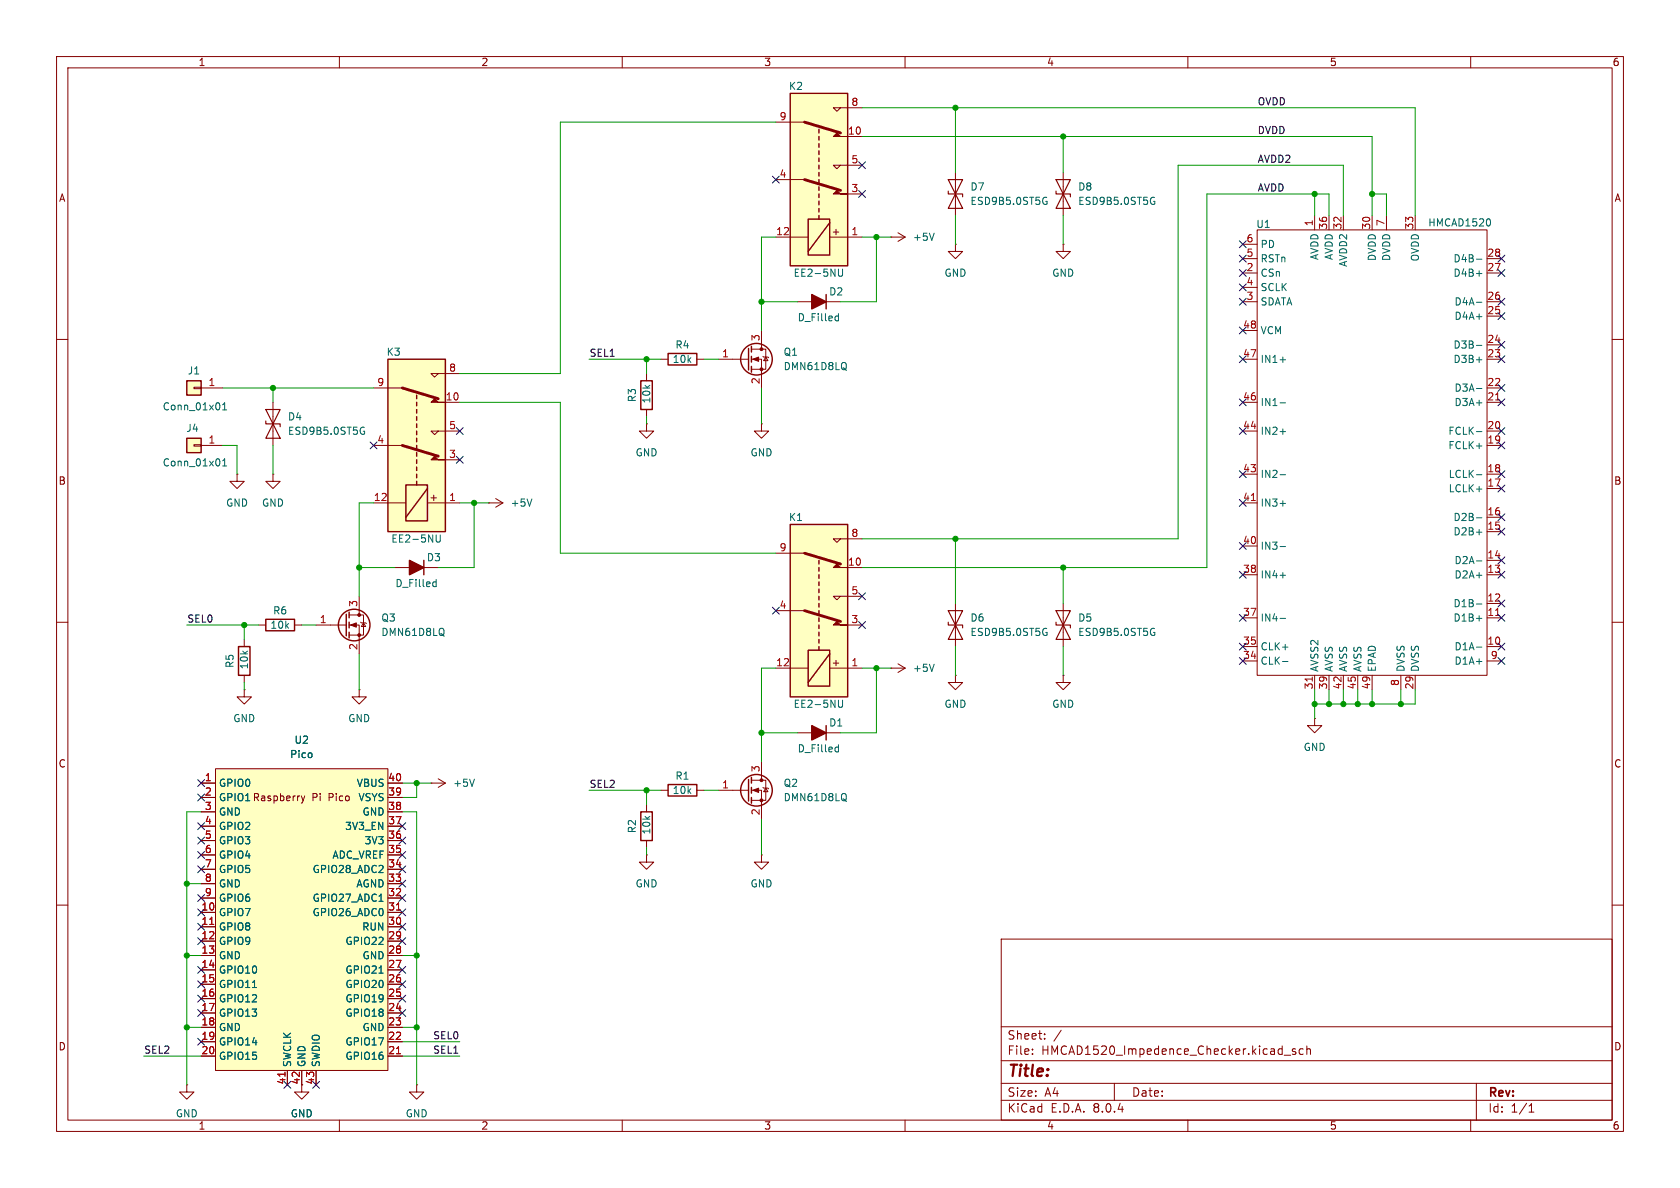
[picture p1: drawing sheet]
<svg xmlns="http://www.w3.org/2000/svg" width="297mm" height="210mm" viewBox="0 0 297 210" stroke-linecap="round" stroke-linejoin="round" font-family="sans-serif">
<defs><g id="words">
<text font-size="2.8" fill="#840000" x="178" y="190.9">Title:</text>
<g font-size="2.1" fill="#840000">
<text x="178" y="184">Sheet:</text>
<text x="178" y="186.7">File:</text>
<text x="184.1" y="186.7">HMCAD1520_Impedence_Checker.kicad_sch</text>
<text x="178" y="196.9">KiCad</text>
<text x="178" y="194.1">Size:</text>
<text x="184.7" y="194.1">A4</text>
<text x="185.7" y="196.9">E.D.A.</text>
<text x="193.3" y="196.9">8.0.4</text>
<text x="200" y="194.1">Date:</text>
<text x="263" y="194.3">Rev:</text>
<text x="263" y="196.9">Id:</text>
<text x="267.1" y="196.9">1/1</text>
</g>
<g font-size="1.8" fill="#840000">
<text x="35" y="11.9">1</text>
<text x="85" y="11.9">2</text>
<text x="135" y="11.9">3</text>
<text x="185" y="11.9">4</text>
<text x="235" y="11.9">5</text>
<text x="285" y="11.9">6</text>
<text x="10.3" y="35.9">A</text>
<text x="285.3" y="35.9">A</text>
<text x="148.6" y="41.9" transform="rotate(-90 148.6 41.9)">+</text>
<text x="10.3" y="85.9">B</text>
<text x="77.5" y="88.9" transform="rotate(-90 77.5 88.9)">+</text>
<text x="285.3" y="85.9">B</text>
<text x="148.6" y="118.1" transform="rotate(-90 148.6 118.1)">+</text>
<text x="10.3" y="135.9">C</text>
<text x="285.3" y="135.9">C</text>
<text x="38.6" y="141.8">GPIO1 Raspberry</text>
<text x="55.1" y="141.8">Pi</text>
<text x="58.2" y="141.8">Pico</text>
<text x="10.3" y="185.9">D</text>
<text x="285.3" y="185.9">D</text>
<text x="53.1" y="191.8" transform="rotate(-90 53.1 191.8)">42</text>
<text x="35" y="199.9">1</text>
<text x="85" y="199.9">2</text>
<text x="135" y="199.9">3</text>
<text x="185" y="199.9">4</text>
<text x="235" y="199.9">5</text>
<text x="285" y="199.9">6</text>
</g>
<g font-size="1.8" fill="#006464">
<text x="139.4" y="16.1">K2</text>
<text x="171.5" y="33.9">D7</text>
<text x="190.5" y="33.9">D8</text>
<text x="171.5" y="36.4">ESD9B5.0ST5G</text>
<text x="190.5" y="36.4">ESD9B5.0ST5G</text>
<text x="222" y="40.5">U1</text>
<text x="252.4" y="40.2">HMCAD1520</text>
<text x="161.3" y="42.8">+5V</text>
<text x="222.8" y="46.6">RSTn</text>
<text x="222.8" y="44">PD</text>
<text x="233.3" y="46.1" transform="rotate(-90 233.3 46.1)">AVDD</text>
<text x="235.8" y="46.1" transform="rotate(-90 235.8 46.1)">AVDD</text>
<text x="238.4" y="47.3" transform="rotate(-90 238.4 47.3)">AVDD2</text>
<text x="243.4" y="46.2" transform="rotate(-90 243.4 46.2)">DVDD</text>
<text x="246" y="46.2" transform="rotate(-90 246 46.2)">DVDD</text>
<text x="251.1" y="46.3" transform="rotate(-90 251.1 46.3)">OVDD</text>
<text x="256.9" y="46.6">D4B-</text>
<text x="140.2" y="49.1">EE2-5NU</text>
<text x="146.5" y="52.4">D2</text>
<text x="166.9" y="49.1">GND</text>
<text x="185.9" y="49.1">GND</text>
<text x="222.8" y="49.1">CSn</text>
<text x="222.8" y="51.7">SCLK</text>
<text x="256.9" y="49.1">D4B+</text>
<text x="140.9" y="57">D_Filled</text>
<text x="222.8" y="54.2">SDATA</text>
<text x="222.8" y="59.3">VCM</text>
<text x="257" y="56.7">D4A+</text>
<text x="257" y="54.2">D4A-</text>
<text x="68.3" y="63.1">K3</text>
<text x="118.8" y="64.4">10k</text>
<text x="119.3" y="61.8">R4</text>
<text x="138.4" y="63.1">Q1</text>
<text x="138.4" y="65.6">DMN61D8LQ</text>
<text x="222.8" y="64.4">IN1+</text>
<text x="256.9" y="64.4">D3B+</text>
<text x="256.9" y="61.8">D3B-</text>
<text x="33.1" y="66.4">J1</text>
<text x="112.6" y="71.2" transform="rotate(-90 112.6 71.2)">R3</text>
<text x="115.2" y="71.4" transform="rotate(-90 115.2 71.4)">10k</text>
<text x="222.8" y="72">IN1-</text>
<text x="257" y="72">D3A+</text>
<text x="257" y="69.4">D3A-</text>
<text x="28.7" y="72.7">Conn_01x01</text>
<text x="32.8" y="76.6">J4</text>
<text x="50.8" y="74.5">D4</text>
<text x="50.8" y="77.1">ESD9B5.0ST5G</text>
<text x="222.8" y="77.1">IN2+</text>
<text x="256" y="77.1">FCLK-</text>
<text x="28.7" y="82.7">Conn_01x01</text>
<text x="112.3" y="80.9">GND</text>
<text x="132.6" y="80.9">GND</text>
<text x="256" y="79.6">FCLK+</text>
<text x="39.9" y="89.8">GND</text>
<text x="46.2" y="89.8">GND</text>
<text x="90.2" y="89.8">+5V</text>
<text x="222.8" y="89.8">IN3+</text>
<text x="222.8" y="84.7">IN2-</text>
<text x="256" y="87.2">LCLK+</text>
<text x="256" y="84.7">LCLK-</text>
<text x="139.4" y="92.3">K1</text>
<text x="256.9" y="94.8">D2B+</text>
<text x="256.9" y="92.3">D2B-</text>
<text x="69.1" y="96.1">EE2-5NU</text>
<text x="75.4" y="99.4">D3</text>
<text x="222.8" y="97.4">IN3-</text>
<text x="257" y="99.9">D2A-</text>
<text x="69.8" y="104">D_Filled</text>
<text x="222.8" y="102.5">IN4+</text>
<text x="256.9" y="107.5">D1B-</text>
<text x="257" y="102.5">D2A+</text>
<text x="47.7" y="111.4">10k</text>
<text x="48.2" y="108.8">R6</text>
<text x="67.3" y="110.1">Q3</text>
<text x="67.3" y="112.6">DMN61D8LQ</text>
<text x="171.5" y="110.1">D6</text>
<text x="171.5" y="112.6">ESD9B5.0ST5G</text>
<text x="190.5" y="110.1">D5</text>
<text x="190.5" y="112.6">ESD9B5.0ST5G</text>
<text x="222.8" y="110.1">IN4-</text>
<text x="256.9" y="110.1">D1B+</text>
<text x="41.5" y="118.2" transform="rotate(-90 41.5 118.2)">R5</text>
<text x="44" y="118.4" transform="rotate(-90 44 118.4)">10k</text>
<text x="161.3" y="119">+5V</text>
<text x="222.8" y="117.7">CLK-</text>
<text x="222.8" y="115.2">CLK+</text>
<text x="233.3" y="118.9" transform="rotate(-90 233.3 118.9)">AVSS2</text>
<text x="235.8" y="118.9" transform="rotate(-90 235.8 118.9)">AVSS</text>
<text x="238.4" y="118.9" transform="rotate(-90 238.4 118.9)">AVSS</text>
<text x="240.9" y="118.9" transform="rotate(-90 240.9 118.9)">AVSS</text>
<text x="243.4" y="118.9" transform="rotate(-90 243.4 118.9)">EPAD</text>
<text x="248.5" y="118.9" transform="rotate(-90 248.5 118.9)">DVSS</text>
<text x="251.1" y="118.9" transform="rotate(-90 251.1 118.9)">DVSS</text>
<text x="257" y="115.2">D1A-</text>
<text x="257" y="117.7">D1A+</text>
<text x="140.2" y="125.3">EE2-5NU</text>
<text x="166.9" y="125.3">GND</text>
<text x="185.9" y="125.3">GND</text>
<text x="41.1" y="127.9">GND</text>
<text x="52" y="131.7">U2</text>
<text x="61.5" y="127.9">GND</text>
<text x="146.5" y="128.6">D1</text>
<text x="51.2" y="134.2">Pico</text>
<text x="140.9" y="133.2">D_Filled</text>
<text x="230.4" y="132.9">GND</text>
<text x="38.6" y="139.3">GPIO0</text>
<text x="38.6" y="141.8">GPIO1</text>
<text x="63" y="139.3">VBUS</text>
<text x="63.3" y="141.8">VSYS</text>
<text x="80" y="139.3">+5V</text>
<text x="118.8" y="140.6">10k</text>
<text x="119.3" y="138">R1</text>
<text x="138.4" y="139.3">Q2</text>
<text x="138.4" y="141.8">DMN61D8LQ</text>
<text x="38.6" y="144.4">GND</text>
<text x="38.6" y="146.9">GPIO2</text>
<text x="38.6" y="149.5">GPIO3</text>
<text x="60.9" y="146.9">3V3_EN</text>
<text x="64" y="144.4">GND</text>
<text x="64.4" y="149.5">3V3</text>
<text x="112.6" y="147.4" transform="rotate(-90 112.6 147.4)">R2</text>
<text x="115.2" y="147.6" transform="rotate(-90 115.2 147.6)">10k</text>
<text x="38.6" y="152">GPIO4</text>
<text x="38.6" y="154.5">GPIO5</text>
<text x="55.2" y="154.5">GPIO28_ADC2</text>
<text x="58.7" y="152">ADC_VREF</text>
<text x="38.6" y="157.1">GND</text>
<text x="38.6" y="159.6">GPIO6</text>
<text x="55.2" y="159.6">GPIO27_ADC1</text>
<text x="62.9" y="157.1">AGND</text>
<text x="112.3" y="157.1">GND</text>
<text x="132.6" y="157.1">GND</text>
<text x="38.6" y="162.2">GPIO7</text>
<text x="38.6" y="164.7">GPIO8</text>
<text x="38.6" y="167.2">GPIO9</text>
<text x="55.2" y="162.2">GPIO26_ADC0</text>
<text x="61" y="167.2">GPIO22</text>
<text x="63.9" y="164.7">RUN</text>
<text x="38.6" y="169.8">GND</text>
<text x="38.6" y="172.3">GPIO10</text>
<text x="61" y="172.3">GPIO21</text>
<text x="64" y="169.8">GND</text>
<text x="38.6" y="174.9">GPIO11</text>
<text x="38.6" y="177.4">GPIO12</text>
<text x="38.6" y="179.9">GPIO13</text>
<text x="61" y="179.9">GPIO18</text>
<text x="61" y="177.4">GPIO19</text>
<text x="61" y="174.9">GPIO20</text>
<text x="38.6" y="182.5">GND</text>
<text x="38.6" y="185">GPIO14</text>
<text x="61" y="185">GPIO17</text>
<text x="64" y="182.5">GND</text>
<text x="38.6" y="187.6">GPIO15</text>
<text x="51.7" y="188.7" transform="rotate(-90 51.7 188.7)">SWCLK</text>
<text x="54.2" y="188.7" transform="rotate(-90 54.2 188.7)">GND</text>
<text x="56.7" y="188.7" transform="rotate(-90 56.7 188.7)">SWDIO</text>
<text x="61" y="187.6">GPIO16</text>
<text x="31" y="197.7">GND</text>
<text x="51.3" y="197.7">GND</text>
<text x="71.6" y="197.7">GND</text>
</g>
<g font-size="1.8" fill="#a90000">
<text x="137.7" y="21.3">9</text>
<text x="149.8" y="23.9">10</text>
<text x="150.4" y="18.8">8</text>
<text x="150.4" y="29">5</text>
<text x="137.7" y="31.5">4</text>
<text x="150.4" y="34">3</text>
<text x="137.1" y="41.7">12</text>
<text x="150.4" y="41.7">1</text>
<text x="232.2" y="40.1" transform="rotate(-90 232.2 40.1)">1</text>
<text x="234.7" y="40.7" transform="rotate(-90 234.7 40.7)">36</text>
<text x="237.2" y="40.7" transform="rotate(-90 237.2 40.7)">32</text>
<text x="242.3" y="40.7" transform="rotate(-90 242.3 40.7)">30</text>
<text x="244.9" y="40.1" transform="rotate(-90 244.9 40.1)">7</text>
<text x="249.9" y="40.7" transform="rotate(-90 249.9 40.7)">33</text>
<text x="220.3" y="45.5">5</text>
<text x="220.3" y="42.9">6</text>
<text x="262.8" y="45.5">28</text>
<text x="220.3" y="48">2</text>
<text x="220.3" y="53.1">3</text>
<text x="220.3" y="50.5">4</text>
<text x="262.8" y="53.1">26</text>
<text x="262.8" y="48">27</text>
<text x="219.7" y="58.2">48</text>
<text x="262.8" y="55.6">25</text>
<text x="79.3" y="65.8">8</text>
<text x="127.6" y="63.2">1</text>
<text x="134.4" y="60.4" transform="rotate(-90 134.4 60.4)">3</text>
<text x="219.7" y="63.2">47</text>
<text x="262.8" y="63.2">23</text>
<text x="262.8" y="60.7">24</text>
<text x="36.8" y="68.3">1</text>
<text x="66.6" y="68.3">9</text>
<text x="78.7" y="70.9">10</text>
<text x="134.4" y="68" transform="rotate(-90 134.4 68)">2</text>
<text x="219.7" y="70.9">46</text>
<text x="262.8" y="70.9">21</text>
<text x="262.8" y="68.3">22</text>
<text x="79.3" y="75.9">5</text>
<text x="219.7" y="75.9">44</text>
<text x="262.8" y="75.9">20</text>
<text x="36.8" y="78.5">1</text>
<text x="66.6" y="78.5">4</text>
<text x="79.3" y="81">3</text>
<text x="219.7" y="83.6">43</text>
<text x="262.8" y="83.6">18</text>
<text x="262.8" y="78.5">19</text>
<text x="66" y="88.6">12</text>
<text x="79.3" y="88.6">1</text>
<text x="219.7" y="88.6">41</text>
<text x="262.8" y="86.1">17</text>
<text x="150.4" y="95">8</text>
<text x="262.8" y="93.7">15</text>
<text x="262.8" y="91.2">16</text>
<text x="137.7" y="97.5">9</text>
<text x="149.8" y="100.1">10</text>
<text x="219.7" y="101.3">38</text>
<text x="219.7" y="96.3">40</text>
<text x="262.8" y="101.3">13</text>
<text x="262.8" y="98.8">14</text>
<text x="63.2" y="107.4" transform="rotate(-90 63.2 107.4)">3</text>
<text x="137.7" y="107.7">4</text>
<text x="150.4" y="105.2">5</text>
<text x="262.8" y="106.4">12</text>
<text x="56.4" y="110.2">1</text>
<text x="150.4" y="110.2">3</text>
<text x="219.7" y="109">37</text>
<text x="262.8" y="109">11</text>
<text x="63.2" y="115" transform="rotate(-90 63.2 115)">2</text>
<text x="137.1" y="117.9">12</text>
<text x="150.4" y="117.9">1</text>
<text x="219.7" y="116.6">34</text>
<text x="219.7" y="114">35</text>
<text x="262.8" y="114">10</text>
<text x="263.5" y="116.6">9</text>
<text x="232.2" y="122" transform="rotate(-90 232.2 122)">31</text>
<text x="234.7" y="122" transform="rotate(-90 234.7 122)">39</text>
<text x="237.2" y="122" transform="rotate(-90 237.2 122)">42</text>
<text x="239.8" y="122" transform="rotate(-90 239.8 122)">45</text>
<text x="242.3" y="122" transform="rotate(-90 242.3 122)">49</text>
<text x="247.4" y="121.4" transform="rotate(-90 247.4 121.4)">8</text>
<text x="249.9" y="122" transform="rotate(-90 249.9 122)">29</text>
<text x="134.4" y="136.6" transform="rotate(-90 134.4 136.6)">3</text>
<text x="36.1" y="138.2">1</text>
<text x="36.1" y="140.7">2</text>
<text x="36.1" y="143.3">3</text>
<text x="68.5" y="143.3">38</text>
<text x="68.5" y="140.7">39</text>
<text x="68.5" y="138.2">40</text>
<text x="127.6" y="139.4">1</text>
<text x="36.1" y="145.8">4</text>
<text x="36.1" y="148.3">5</text>
<text x="68.5" y="148.3">36</text>
<text x="68.5" y="145.8">37</text>
<text x="134.4" y="144.2" transform="rotate(-90 134.4 144.2)">2</text>
<text x="36.1" y="150.9">6</text>
<text x="36.1" y="153.4">7</text>
<text x="36.1" y="156">8</text>
<text x="68.5" y="156">33</text>
<text x="68.5" y="153.4">34</text>
<text x="68.5" y="150.9">35</text>
<text x="35.5" y="161">10</text>
<text x="36.1" y="158.5">9</text>
<text x="68.5" y="161">31</text>
<text x="68.5" y="158.5">32</text>
<text x="35.5" y="163.6">11</text>
<text x="35.5" y="166.1">12</text>
<text x="68.5" y="166.1">29</text>
<text x="68.5" y="163.6">30</text>
<text x="35.5" y="168.7">13</text>
<text x="35.5" y="171.2">14</text>
<text x="35.5" y="173.7">15</text>
<text x="68.5" y="173.7">26</text>
<text x="68.5" y="171.2">27</text>
<text x="68.5" y="168.7">28</text>
<text x="35.5" y="176.3">16</text>
<text x="35.5" y="178.8">17</text>
<text x="68.5" y="178.8">24</text>
<text x="68.5" y="176.3">25</text>
<text x="35.5" y="181.4">18</text>
<text x="35.5" y="183.9">19</text>
<text x="68.5" y="183.9">22</text>
<text x="68.5" y="181.4">23</text>
<text x="35.5" y="186.4">20</text>
<text x="50.5" y="191.8" transform="rotate(-90 50.5 191.8)">41</text>
<text x="55.6" y="191.8" transform="rotate(-90 55.6 191.8)">43</text>
<text x="68.5" y="186.4">21</text>
</g>
<g font-size="1.8" fill="#0f0f0f">
<text x="222.2" y="23.8">DVDD</text>
<text x="222.2" y="18.7">OVDD</text>
<text x="222.2" y="28.9">AVDD2</text>
<text x="222.2" y="33.9">AVDD</text>
<text x="104.1" y="63.2">SEL1</text>
<text x="33" y="110.1">SEL0</text>
<text x="104.1" y="139.4">SEL2</text>
<text x="76.5" y="183.8">SEL0</text>
<text x="25.4" y="186.3">SEL2</text>
<text x="76.5" y="186.3">SEL1</text>
</g>
</g></defs>
<g fill="none" stroke="#840000" stroke-width=".18">
<path d="M10 10h277v190h-277zM12 12h273v186h-273zM60 10v2M110 10v2M160 10v2M210 10v2M260 10v2M10 60h2M141 53.3h7.6M285 60h2M114.3 66v1.3M114.3 72.4v1.3"/>
<path d="M116.8 63.5h1.3M123.2 63.5h1.3M134.6 74.9v1.3h1.3l-1.3 1.3-1.3-1.3h1.3M134.6 74.9h.1M10 110h2M43.2 113v1.3M43.2 119.4v1.3M45.7 110.5h1.3M52.1 110.5h1.2M55.9 110.5h5.3M61.7 110.5h1.8v5.1M61.7 108.7h2.6v3.6h-2.6"/>
<path d="M63.5 105.4v3.3M63.8 110l.1 .1h.7l.2 .1M64.3 110.1l.3 .6h-.7zM69.8 100.3h7.7M285 110h2M43.2 121.9v1.3h1.2l-1.2 1.3-1.3-1.3h1.3M43.2 121.9h.1M63.5 121.9v1.3h1.3l-1.3 1.3-1.3-1.3h1.3M63.5 121.9h.1M76.2 138.4h.1M76.2 138.4h2.5M77.5 137.7l1.2 .7"/>
<path d="M78.7 138.4l-1.2 .8M232.4 127v1.3h1.3l-1.3 1.2-1.3-1.2h1.3M232.4 127h.1M10 160h2M114.3 151.1v1.3h1.3l-1.3 1.3-1.3-1.3h1.3M114.3 151.1h.1M134.6 151.1v1.3h1.3l-1.3 1.3-1.3-1.3h1.3M134.6 151.1h.1M285 160h2M177 166h108v32h-108zM60 198v2M110 198v2"/>
<path d="M160 198v2M177 194.5h108M177 191.5h108M177 187.5h108M177 181.5h108M182.5 186.3v.1M182.5 185.5v.1M184.7 183.6v.1M184.7 182.8v.1M187.6 182.1l-1.3 2M197 191.5v3M210 198v2"/>
<path d="M227 186.5h1.2M229 185.5l-.3-.1-.2 .2v.2l.5 .2v.3h-.5M230.4 185.5l-.4-.1-.3 .3v.4l.1 .2h.6M231 185.5l.2-.1 .4 .1 .1 .9M231 184.9v1.5M260 198v2M261 191.5v6.5M270.3 196.6h.9M270.3 195.5l.4-.4v1.5"/>
</g>
<g fill="none" stroke="#840000" stroke-width=".25">
<path d="M146 52.1v2.5M113.3 67.3h2v5.1h-2zM118.1 62.5h5.1v2h-5.1zM74.9 99.1v2.5M42.2 114.3h2v5.1h-2zM47 109.5h5.1v2h-5.1zM61.2 108.6v3.8M61.7 108.2v1M61.7 110v1M61.7 111.8v1"/>
<circle cx="62.6" cy="110.5" r="2.79"/>
</g>
<g fill="#840000" stroke="#840000" stroke-width=".18">
<path d="M62 110.5l1-.4v.8z"/>
<circle cx="63.5" cy="112.3" r=".25"/>
<circle cx="63.5" cy="108.7" r=".25"/>
</g>
<path d="M147.9 55.9h.3M148.2 55.4v1.3M148.2 56.7h-.3M76.7 102.9h.4M77.1 102.4v1.3M77.1 103.6l-.4 .1M78.4 112.4l.1 .1M78.4 111.3v.9M83.9 137.7l-.5 1.3" fill="none" stroke="#006464" stroke-width=".18"/>
<g fill="#840000" stroke="#840000" stroke-width=".25">
<path d="M72.4 99.1l2.5 1.2-2.5 1.3z"/>
<path d="M143.5 52.1l2.5 1.2-2.5 1.3z"/>
</g>
<path d="M38.1 135.9h30.5v53.3h-30.5z" fill="#ffffc2"/>
<g fill="none" stroke="#840000" stroke-width=".18">
<path d="M134.6 58.4v3.3M114.3 74.9v1.3h1.3l-1.3 1.3-1.3-1.3h1.3M114.3 74.9h.1M127 63.5h5.3M132.8 63.5h1.8v5.1M132.8 61.7h2.6v3.6h-2.6M134.9 63l.1 .1h.8l.1 .1M135.4 63.1l.4 .7h-.8zM48.3 83.8v1.3h1.2l-1.2 1.3-1.3-1.3h1.3M48.3 83.8h.1M86.4 88.9h.1M86.4 88.9h2.5"/>
<path d="M87.6 88.1l1.3 .8M88.9 88.9l-1.3 .8M35.6 138.4h2.5M38.1 135.9h30.5v53.3h-30.5zM68.6 138.4h2.5M35.6 141h2.5M35.6 143.5h2.5M35.6 158.8h2.5M35.6 156.2h2.5M35.6 153.7h2.5M35.6 151.1h2.5M35.6 148.6h2.5"/>
<path d="M35.6 146.1h2.5M53.3 140.7l.3 .8M53.6 141.5l-.3 .5M53.9 140.7l-.3 .8M68.6 141h2.5M68.6 143.5h2.5M68.6 158.8h2.5M68.6 156.2h2.5M68.6 153.7h2.5M68.6 151.1h2.5M68.6 148.6h2.5M68.6 146.1h2.5"/>
<path d="M35.6 161.3h2.5M35.6 163.8h2.5M35.6 166.4h2.5M35.6 168.9h2.5M35.6 171.5h2.5M35.6 174h2.5M35.6 176.5h2.5M35.6 179.1h2.5M68.6 161.3h2.5M68.6 163.8h2.5M68.6 166.4h2.5M68.6 168.9h2.5"/>
<path d="M68.6 171.5h2.5M68.6 174h2.5M68.6 176.5h2.5M68.6 179.1h2.5M35.6 181.6h2.5M35.6 184.2h2.5M35.6 186.7h2.5M50.8 189.2v2.6M53.3 189.2v2.6M55.9 189.2v2.6M68.6 181.6h2.5M68.6 184.2h2.5"/>
<path d="M68.6 186.7h2.5"/>
</g>
<path d="M37.1 163.4h.7M70.1 160.9h.7M50.4 189.5v.8M70.1 186.3h.7" fill="none" stroke="#a90000" stroke-width=".18"/>
<path d="M149.5 65.4l.2 .1M149.5 64.3v.9M94 88.2l-.4 1.3M67 159.3h.7M44.6 174.6h.8M67 172h.7" fill="none" stroke="#006464" stroke-width=".18"/>
<g fill="none" stroke="#840000" stroke-width=".25">
<path d="M132.3 61.6v3.8M132.8 61.2v1M132.8 63v1M132.8 64.8v1"/>
<circle cx="133.7" cy="63.5" r="2.79"/>
</g>
<g fill="#840000" stroke="#840000" stroke-width=".18">
<path d="M133.1 63.5l1-.4v.8z"/>
<circle cx="134.6" cy="65.3" r=".25"/>
<circle cx="134.6" cy="61.7" r=".25"/>
</g>
<path d="M33 67.3h2.6v2.6h-2.6z" fill="#ffffc2"/>
<path d="M34.3 68.5h1.3v.2h-1.3zM35.6 68.6h3.8" fill="none" stroke="#840000" stroke-width=".18"/>
<path d="M33 67.3h2.6v2.6h-2.6z" fill="none" stroke="#840000" stroke-width=".25"/>
<path d="M39.4 72.5h.7M39.4 71.6l.3-.4v1.3" fill="none" stroke="#006464" stroke-width=".18"/>
<path d="M33 77.5h2.6v2.5h-2.6z" fill="#ffffc2"/>
<g fill="none" stroke="#840000" stroke-width=".18">
<path d="M157.5 41.9h.1M157.5 41.9h2.5M158.7 41.1l1.3 .8M160 41.9l-1.3 .8M34.3 78.6h1.3v.3h-1.3zM35.6 78.7h3.8M41.9 83.8v1.3h1.3l-1.3 1.3-1.3-1.3h1.3M41.9 83.8h.1M168.9 119.4v1.3h1.3l-1.3 1.2-1.3-1.2h1.3M168.9 119.4h.1M188 119.4v1.3h1.2l-1.2 1.2-1.3-1.2h1.3M188 119.4h.1"/>
<path d="M33 191.8v1.2h1.3l-1.3 1.3-1.3-1.3h1.3M33 191.8h.1M53.3 191.8v1.2h1.3l-1.3 1.3-1.2-1.3h1.2"/>
</g>
<path d="M33 77.5h2.6v2.5h-2.6z" fill="none" stroke="#840000" stroke-width=".25"/>
<path d="M165.2 41.2l-.5 1.3M39.4 82.4h.7M39.4 81.5l.3-.4v1.3" fill="none" stroke="#006464" stroke-width=".18"/>
<path d="M139.7 92.7h10.2v30.5h-10.2z" fill="#ffffc2"/>
<g fill="none" stroke="#840000" stroke-width=".25">
<path d="M139.7 92.7h10.2v30.5h-10.2zM144.8 99.1v.6M142.9 114.9h3.8v6.4h-3.8zM144.8 100.3v.7M144.8 101.6v.6M144.8 102.9v.6M144.8 104.1v.7M144.8 105.4v.6M144.8 106.7v.6M144.8 108v.6M144.8 109.2v.7M144.8 110.5v.6"/>
<path d="M144.8 111.8v.6M144.8 113v.7M144.8 114.3v.6M146.7 115.6l-3.8 5.1"/>
</g>
<path d="M168.9 43.2v1.3h1.3l-1.3 1.2-1.3-1.2h1.3M168.9 43.2h.1M137.2 97.8h5M148.6 95.3l-.6 .6-.7-.6h5.1M137.2 118.1h5.7M137.2 108h5M146.7 118.1h5.7M148.6 105.4l-.6 .6-.7-.6h5.1M149.9 100.3h2.5M149.9 110.5h2.5M188 106.7v7.6" fill="none" stroke="#840000" stroke-width=".18"/>
<path d="M142.2 97.8l6.4 1.9M142.2 108l6.4 1.9" fill="none" stroke="#840000" stroke-width=".51"/>
<g fill="#840000" stroke="#840000" stroke-width=".18">
<path d="M148 109.9l.6 .6h1.3h-2.6z"/>
<path d="M148 99.7l.6 .6h1.3h-2.6z"/>
</g>
<path d="M203.8 111.1h.3M203.9 111.8h.3v.4l-.4 .1M148.2 123.8v1l.3 .2h.2l.3-.2v-1" fill="none" stroke="#006464" stroke-width=".18"/>
<path d="M186.7 110v.5h2.5v.5M186.7 108h2.5l-1.2 2.5zM188 110.5l1.2 2.5h-2.5z" fill="none" stroke="#840000" stroke-width=".2"/>
<path d="M68.6 63.5h10.1v30.5h-10.1z" fill="#ffffc2"/>
<g fill="none" stroke="#840000" stroke-width=".25">
<path d="M68.6 63.5h10.1v30.5h-10.1zM73.7 69.9v.6M73.7 71.1v.7M73.7 72.4v.6M73.7 73.7v.6M73.7 74.9v.7M73.7 76.2v.6M73.7 77.5v.6M73.7 78.7v.7M71.8 85.7h3.8v6.4h-3.8zM73.7 80v.6M73.7 81.3v.6"/>
<path d="M73.7 82.6v.6M73.7 83.8v.7M73.7 85.1v.6M75.6 86.4l-3.8 5M118.1 138.7h5.1v2h-5.1z"/>
</g>
<path d="M168.9 30.5v7.6M66 78.7h5.1M66 68.6h5.1M77.5 76.2l-.7 .6-.6-.6h5.1M77.5 66l-.7 .7-.6-.7h5.1M78.7 71.1h2.6M66 88.9h5.8M75.6 88.9h5.7M78.7 81.3h2.6M116.8 139.7h1.3M123.2 139.7h1.3" fill="none" stroke="#840000" stroke-width=".18"/>
<path d="M71.1 78.7l6.4 1.9M71.1 68.6l6.4 1.9" fill="none" stroke="#840000" stroke-width=".51"/>
<g fill="#840000" stroke="#840000" stroke-width=".18">
<path d="M76.2 81.3l.6-.7 .7 .7h1.2z"/>
<path d="M76.2 71.1l.6-.6 .7 .6h1.2z"/>
</g>
<path d="M184.7 34.9h.3M184.9 35.6h.2v.4l-.4 .1M77.1 94.6v1l.2 .2h.3l.2-.2v-1" fill="none" stroke="#006464" stroke-width=".18"/>
<path d="M167.6 33.8v.5h2.6v.5M167.6 31.8h2.6l-1.3 2.5zM168.9 34.3l1.3 2.5h-2.6z" fill="none" stroke="#840000" stroke-width=".2"/>
<path d="M139.7 16.5h10.2v30.5h-10.2z" fill="#ffffc2"/>
<g fill="none" stroke="#840000" stroke-width=".25">
<path d="M139.7 16.5h10.2v30.5h-10.2zM142.9 38.7h3.8v6.4h-3.8zM144.8 22.9v.6M144.8 24.1v.7M144.8 25.4v.6M144.8 26.7v.6M144.8 27.9v.7M144.8 29.2v.6M144.8 30.5v.6M144.8 31.8v.6M144.8 33v.7M144.8 34.3v.6"/>
<path d="M144.8 35.6v.6M144.8 36.8v.7M144.8 38.1v.6M146.7 39.4l-3.8 5.1M132.3 137.8v3.8M132.8 137.4v1M132.8 139.2v1M146 128.3v2.5M113.3 143.5h2v5.1h-2zM132.8 141v1"/>
<circle cx="133.7" cy="139.7" r="2.79"/>
</g>
<g fill="none" stroke="#840000" stroke-width=".18">
<path d="M148.6 19.1l-.6 .6-.7-.6h5.1M137.2 31.8h5M137.2 21.6h5M148.6 29.2l-.6 .6-.7-.6h5.1M149.9 24.1h2.5M149.9 34.3h2.5M188 30.5v7.6M232.4 38.1v2.5M234.9 38.1v2.5M237.5 38.1v2.5M242.6 38.1v2.5M245.1 38.1v2.5"/>
<path d="M250.2 38.1v2.5M137.2 41.9h5.7M146.7 41.9h5.7M188 43.2v1.3h1.2l-1.2 1.2-1.3-1.2h1.3M188 43.2h.1M219.7 48.3h2.5M219.7 53.3h2.5M219.7 45.7h2.5M219.7 50.8h2.5M219.7 58.4h2.5M219.7 43.2h2.5M222.2 40.6h40.7v78.8h-40.7z"/>
<path d="M262.9 48.3h2.5M262.9 55.9h2.5M262.9 53.3h2.5M262.9 45.7h2.5M48.3 71.1v7.6M219.7 76.2h2.5M219.7 71.1h2.5M219.7 63.5h2.5M262.9 78.7h2.5M262.9 76.2h2.5M262.9 71.1h2.5M262.9 68.6h2.5"/>
<path d="M262.9 63.5h2.5M262.9 61h2.5M219.7 83.8h2.5M219.7 96.5h2.5M219.7 88.9h2.5M262.9 99.1h2.5M262.9 94h2.5M262.9 91.4h2.5M262.9 86.4h2.5M262.9 83.8h2.5M157.5 118.1h.1M157.5 118.1h2.5"/>
<path d="M158.7 117.3l1.3 .8M160 118.1l-1.3 .8M168.9 106.7v7.6M219.7 114.3h2.5M219.7 109.2h2.5M219.7 101.6h2.5M219.7 116.8h2.5M232.4 119.4v2.5M234.9 119.4v2.5M237.5 119.4v2.5M240 119.4v2.5M242.6 119.4v2.5"/>
<path d="M247.6 119.4v2.5M250.2 119.4v2.5M262.9 114.3h2.5M262.9 109.2h2.5M262.9 106.7h2.5M262.9 101.6h2.5M262.9 116.8h2.5M35.6 138.4h2.5M68.6 138.4h2.5M127 139.7h5.3M132.8 139.7h1.8v5.1M132.8 137.9h2.6v3.6h-2.6"/>
<path d="M134.6 134.6v3.3M134.9 139.2l.1 .1h.8l.1 .1M135.4 139.3l.4 .7h-.8zM141 129.5h7.6M35.6 141h2.5M35.6 143.5h2.5M35.6 158.8h2.5M35.6 156.2h2.5M35.6 153.7h2.5M35.6 151.1h2.5M35.6 148.6h2.5M35.6 146.1h2.5"/>
<path d="M68.6 141h2.5M68.6 143.5h2.5M68.6 158.8h2.5M68.6 156.2h2.5M68.6 153.7h2.5M68.6 151.1h2.5M68.6 148.6h2.5M68.6 146.1h2.5M114.3 142.2v1.3M114.3 148.6v1.3M35.6 161.3h2.5M35.6 163.8h2.5"/>
<path d="M35.6 166.4h2.5M35.6 168.9h2.5M35.6 171.5h2.5M35.6 174h2.5M35.6 176.5h2.5M35.6 179.1h2.5M68.6 161.3h2.5M68.6 163.8h2.5M68.6 166.4h2.5M68.6 168.9h2.5M68.6 171.5h2.5M68.6 174h2.5"/>
<path d="M68.6 176.5h2.5M68.6 179.1h2.5M35.6 181.6h2.5M35.6 184.2h2.5M35.6 186.7h2.5M50.8 189.2v2.6M53.3 189.2v2.6M55.9 189.2v2.6M68.6 181.6h2.5M68.6 184.2h2.5M68.6 186.7h2.5M73.7 191.8v1.2h1.2l-1.2 1.3-1.3-1.3h1.3"/>
<path d="M73.7 191.8h.1"/>
</g>
<path d="M142.2 31.8l6.4 1.9M142.2 21.6l6.4 1.9" fill="none" stroke="#840000" stroke-width=".51"/>
<g fill="#840000" stroke="#840000" stroke-width=".18">
<path d="M148 33.7l.6 .6h1.3h-2.6z"/>
<path d="M147.3 24.1l.7-.6 .6 .6h1.3z"/>
<path d="M133.1 139.7l1-.4v.8z"/>
<circle cx="134.6" cy="141.5" r=".25"/>
<circle cx="134.6" cy="137.9" r=".25"/>
</g>
<g fill="none" stroke="#006464" stroke-width=".18">
<path d="M203.8 34.9h.3M203.9 35.6h.3v.4l-.4 .1M263.3 38.7l.2 .5-.2 .7M148.2 47.6v1l.3 .2h.2l.3-.2v-1M261 53.4h1M261 48.4h1M261 45.8h1M64.1 75.5l.3 .1M64.2 76.2h.3v.5l-.4 .1M226.3 76.3h1M226.3 63.6h1M226.3 71.2h1"/>
<path d="M261 76.3h1M261 68.7h1M261 63.6h1M261 61.1h1M226.3 83.9h1M226.3 96.6h1M226.3 89h1M261 99.2h1M261 94.1h1M261 91.5h1M261 83.9h1M165.2 117.4l-.5 1.3"/>
<path d="M184.7 111.1h.3M184.9 111.8h.2v.4l-.4 .1M226.3 109.3h1M226.3 101.7h1M226.7 116.9h1M261 114.4h1M261 109.3h1M261 106.8h1M147.9 132.1h.3M148.2 131.6v1.3M148.2 132.9h-.3M67 159.3h.7"/>
<path d="M149.5 141.6l.2 .1M149.5 140.5v.9M44.6 174.6h.8M67 172h.7"/>
</g>
<path d="M186.7 33.8v.5h2.5v.5M186.7 31.8h2.5l-1.2 2.5zM188 34.3l1.2 2.5h-2.5zM47 74.4v.5h2.5v.5M47 72.4h2.5l-1.2 2.5zM48.3 74.9l1.2 2.6h-2.5zM167.6 110v.5h2.6v.5M167.6 108h2.6l-1.3 2.5zM168.9 110.5l1.3 2.5h-2.6z" fill="none" stroke="#840000" stroke-width=".2"/>
<path d="M264.4 70.7h.7M221.2 88.5h.7M232 119.7v.7M264.4 108.8h.7M37.1 163.4h.7M70.1 160.9h.7M50.4 189.5v.8M70.1 186.3h.7" fill="none" stroke="#a90000" stroke-width=".18"/>
<path d="M143.5 128.3l2.5 1.2-2.5 1.3z" fill="#840000" stroke="#840000" stroke-width=".25"/>
<g fill="none" stroke="#009600" stroke-width=".18">
<path d="M152.4 19.1h97.8v19M168.9 19.1v11.4M137.2 21.6h-38.1v44.4h-17.8M152.4 24.1h90.2v14M168.9 38.1v5.1M188 24.1v6.4M188 38.1v5.1M232.4 34.3v3.8M234.9 38.1v-3.8h-21.5v66h-61M237.5 38.1v-8.9h-29.2v66.1h-55.9M242.6 34.3h2.5v3.8M134.6 53.3h6.4"/>
<path d="M137.2 41.9h-2.6v16.5M152.4 41.9h5.1M154.9 41.9v11.4h-6.3M39.4 78.7h2.5v5.1M39.4 68.6h26.6M48.3 68.6v2.5M48.3 78.7v5.1M81.3 71.1h17.8v26.7h38.1M104.1 63.5h12.7M114.3 63.5v2.5M114.3 73.7v1.2M124.5 63.5h2.5"/>
<path d="M134.6 68.6v6.3M66 88.9h-2.5v16.5M81.3 88.9h5.1M83.8 88.9v11.4h-6.3M168.9 95.3v11.4M33 110.5h12.7M43.2 110.5v2.5M53.3 110.5h2.6M63.5 100.3h6.3M63.5 115.6v6.3M137.2 118.1h-2.6v16.5M152.4 118.1h5.1"/>
<path d="M154.9 118.1v11.4h-6.3M168.9 114.3v5.1M188 100.3v6.4M188 114.3v5.1M43.2 120.7v1.2M71.1 138.4h5.1M73.7 138.4v2.6h-2.6M104.1 139.7h12.7M114.3 139.7v2.5M124.5 139.7h2.5M134.6 129.5h6.4M232.4 121.9v5.1"/>
<path d="M234.9 121.9v2.6M237.5 121.9v2.6M240 121.9v2.6M242.6 121.9v2.6M247.6 121.9v2.6M250.2 121.9v2.6h-17.8M33 156.2h2.6M35.6 143.5h-2.6v48.3M71.1 143.5h2.6v48.3M114.3 149.9v1.2M134.6 144.8v6.3M33 168.9h2.6"/>
<path d="M71.1 168.9h2.6M25.4 186.7h10.2M33 181.6h2.6M71.1 181.6h2.6M71.1 184.2h10.2M71.1 186.7h10.2"/>
</g>
<g fill="none" stroke="#000084" stroke-width=".18">
<path d="M136.6 31.1l1.2 1.3M137.8 31.1l-1.2 1.3M151.8 28.6l1.2 1.2M151.8 33.7l1.2 1.2M153 33.7l-1.2 1.2M153 28.6l-1.2 1.2M219.1 57.8l1.2 1.2M219.1 52.7l1.2 1.2M219.1 50.2l1.2 1.2M219.1 47.7l1.2 1.2M219.1 45.1l1.2 1.2M219.1 42.6l1.2 1.2"/>
<path d="M220.3 57.8l-1.2 1.2M220.3 52.7l-1.2 1.2M220.3 50.2l-1.2 1.2M220.3 47.7l-1.2 1.2M220.3 45.1l-1.2 1.2M220.3 42.6l-1.2 1.2M264.8 55.3l1.2 1.2M264.8 52.7l1.2 1.2M264.8 47.7l1.2 1.2M264.8 45.1l1.2 1.2M266 55.3l-1.2 1.2M266 52.7l-1.2 1.2"/>
<path d="M266 47.7l-1.2 1.2M266 45.1l-1.2 1.2M65.4 78.1l1.2 1.2M66.6 78.1l-1.2 1.2M80.7 75.6l1.2 1.2M81.9 75.6l-1.2 1.2M219.1 70.5l1.2 1.2M219.1 75.6l1.2 1.2M219.1 62.9l1.2 1.2M220.3 70.5l-1.2 1.2M220.3 75.6l-1.2 1.2M220.3 62.9l-1.2 1.2"/>
<path d="M264.8 68l1.2 1.2M264.8 78.1l1.2 1.2M264.8 70.5l1.2 1.2M264.8 75.6l1.2 1.2M264.8 60.4l1.2 1.2M264.8 62.9l1.2 1.2M266 62.9l-1.2 1.2M266 68l-1.2 1.2M266 70.5l-1.2 1.2M266 78.1l-1.2 1.2M266 75.6l-1.2 1.2M266 60.4l-1.2 1.2"/>
<path d="M80.7 80.7l1.2 1.2M81.9 80.7l-1.2 1.2M219.1 95.9l1.2 1.2M219.1 88.3l1.2 1.2M219.1 83.2l1.2 1.2M220.3 95.9l-1.2 1.2M220.3 88.3l-1.2 1.2M220.3 83.2l-1.2 1.2M264.8 85.8l1.2 1.2M264.8 98.5l1.2 1.2M264.8 93.4l1.2 1.2M264.8 83.2l1.2 1.2"/>
<path d="M264.8 90.8l1.2 1.2M266 85.8l-1.2 1.2M266 98.5l-1.2 1.2M266 93.4l-1.2 1.2M266 83.2l-1.2 1.2M266 90.8l-1.2 1.2M136.6 107.3l1.2 1.3M137.8 107.3l-1.2 1.3M151.8 104.8l1.2 1.2M151.8 109.9l1.2 1.2M153 104.8l-1.2 1.2M153 109.9l-1.2 1.2"/>
<path d="M219.1 108.6l1.2 1.2M219.1 113.7l1.2 1.2M219.1 116.2l1.2 1.2M219.1 101l1.2 1.2M220.3 108.6l-1.2 1.2M220.3 113.7l-1.2 1.2M220.3 116.2l-1.2 1.2M220.3 101l-1.2 1.2M264.8 113.7l1.2 1.2M264.8 116.2l1.2 1.2M264.8 108.6l1.2 1.2M264.8 101l1.2 1.2"/>
<path d="M264.8 106.1l1.2 1.2M266 113.7l-1.2 1.2M266 116.2l-1.2 1.2M266 108.6l-1.2 1.2M266 101l-1.2 1.2M266 106.1l-1.2 1.2M35 137.8l1.2 1.2M36.2 137.8l-1.2 1.2M35 158.1l1.2 1.3M35 150.5l1.2 1.2M35 153.1l1.2 1.2M35 145.4l1.2 1.3"/>
<path d="M35 148l1.2 1.2M35 140.4l1.2 1.2M36.2 158.1l-1.2 1.3M36.2 150.5l-1.2 1.2M36.2 153.1l-1.2 1.2M36.2 145.4l-1.2 1.3M36.2 148l-1.2 1.2M36.2 140.4l-1.2 1.2M70.5 150.5l1.2 1.2M70.5 158.1l1.2 1.3M70.5 148l1.2 1.2M70.5 153.1l1.2 1.2"/>
<path d="M70.5 155.6l1.2 1.2M70.5 145.4l1.2 1.3M71.7 148l-1.2 1.2M71.7 150.5l-1.2 1.2M71.7 158.1l-1.2 1.3M71.7 153.1l-1.2 1.2M71.7 155.6l-1.2 1.2M71.7 145.4l-1.2 1.3M35 175.9l1.2 1.2M35 173.4l1.2 1.2M35 163.2l1.2 1.2M35 160.7l1.2 1.2"/>
<path d="M35 165.8l1.2 1.2M35 170.8l1.2 1.3M35 178.5l1.2 1.2M36.2 175.9l-1.2 1.2M36.2 173.4l-1.2 1.2M36.2 163.2l-1.2 1.2M36.2 160.7l-1.2 1.2M36.2 165.8l-1.2 1.2M36.2 170.8l-1.2 1.3M36.2 178.5l-1.2 1.2M70.5 173.4l1.2 1.2M70.5 175.9l1.2 1.2"/>
<path d="M70.5 170.8l1.2 1.3M70.5 178.5l1.2 1.2M70.5 160.7l1.2 1.2M70.5 163.2l1.2 1.2M70.5 165.8l1.2 1.2M71.7 173.4l-1.2 1.2M71.7 175.9l-1.2 1.2M71.7 170.8l-1.2 1.3M71.7 178.5l-1.2 1.2M71.7 160.7l-1.2 1.2M71.7 163.2l-1.2 1.2M71.7 165.8l-1.2 1.2"/>
<path d="M35 183.5l1.2 1.3M36.2 183.5l-1.2 1.3M50.2 191.2l1.2 1.2M51.4 191.2l-1.2 1.2M55.3 191.2l1.2 1.2M56.5 191.2l-1.2 1.2"/>
</g>
<g fill="#009600" stroke="#009600" stroke-width=".18">
<circle cx="33" cy="168.9" r=".46"/>
<circle cx="73.7" cy="181.6" r=".46"/>
<circle cx="33" cy="181.6" r=".46"/>
<circle cx="73.7" cy="168.9" r=".46"/>
<circle cx="33" cy="156.2" r=".46"/>
<circle cx="43.2" cy="110.5" r=".46"/>
<circle cx="48.3" cy="68.6" r=".46"/>
<circle cx="63.5" cy="100.3" r=".46"/>
<circle cx="114.3" cy="63.5" r=".46"/>
<circle cx="73.7" cy="138.4" r=".46"/>
<circle cx="83.8" cy="88.9" r=".46"/>
<circle cx="134.6" cy="129.5" r=".46"/>
<circle cx="114.3" cy="139.7" r=".46"/>
<circle cx="234.9" cy="124.5" r=".46"/>
<circle cx="232.4" cy="124.5" r=".46"/>
<circle cx="242.6" cy="124.5" r=".46"/>
<circle cx="247.6" cy="124.5" r=".46"/>
<circle cx="237.5" cy="124.5" r=".46"/>
<circle cx="240" cy="124.5" r=".46"/>
<circle cx="154.9" cy="41.9" r=".46"/>
<circle cx="134.6" cy="53.3" r=".46"/>
<circle cx="168.9" cy="95.3" r=".46"/>
<circle cx="154.9" cy="118.1" r=".46"/>
<circle cx="188" cy="24.1" r=".46"/>
<circle cx="242.6" cy="34.3" r=".46"/>
<circle cx="232.4" cy="34.3" r=".46"/>
<circle cx="188" cy="100.3" r=".46"/>
<circle cx="168.9" cy="19.1" r=".46"/>
</g>
<use href="#words"/>
</svg>
